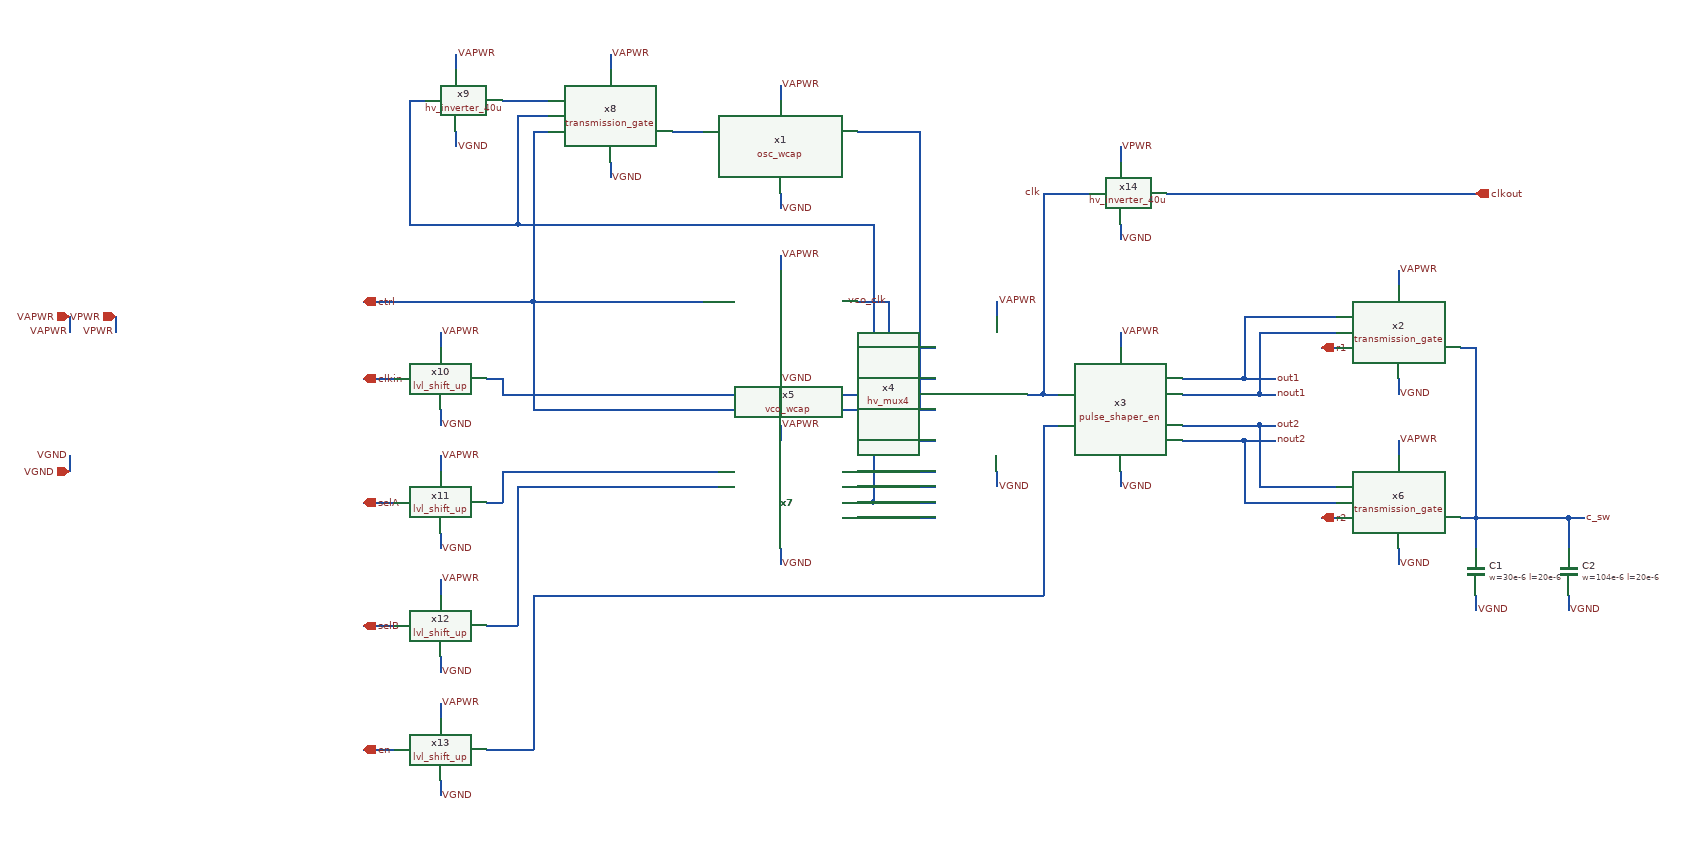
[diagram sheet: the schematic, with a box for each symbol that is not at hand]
v {xschem version=3.4.8RC file_version=1.3}
G {}
K {}
V {}
S {}
F {}
E {}
N 560 260 560 280 {lab=VGND}
N -1260 80 -1260 100 {lab=VGND}
N -1260 -100 -1260 -80 {lab=VAPWR}
N 540 -60 560 -60 {lab=c_sw
}
N 360 -60 380 -60 {lab=r1
}
N 0 0 20 0 {lab=clk}
N 540 160 560 160 {lab=c_sw
}
N 360 160 380 160 {lab=r2
}
N 560 160 560 200 {lab=c_sw}
N 560 -60 560 160 {lab=c_sw
}
N 260 -100 380 -100 {lab=out1}
N -660 -120 -440 -120 {lab=ctrl}
N 180 -20 260 -20 {lab=out1}
N 260 -100 260 -20 {lab=out1}
N 180 0 280 0 {lab=nout1}
N 280 -80 280 0 {lab=nout1}
N 280 -80 380 -80 {lab=nout1}
N 180 60 260 60 {lab=nout2}
N 260 60 260 140 {lab=nout2}
N 260 140 380 140 {lab=nout2}
N 180 40 280 40 {lab=out2}
N 280 40 280 120 {lab=out2}
N 280 120 380 120 {lab=out2}
N -240 -120 -200 -120 {lab=#net1}
N -200 -120 -200 -20 {lab=#net1}
N -200 -20 -140 -20 {lab=#net1}
N -240 -340 -160 -340 {lab=#net2}
N -160 -340 -160 20 {lab=#net2}
N 0 40 0 260 {lab=#net3}
N 0 40 20 40 {lab=#net3}
N -260 100 -140 100 {lab=#net4}
N -260 120 -140 120 {lab=#net5}
N -220 140 -140 140 {lab=#net6}
N -260 160 -140 160 {lab=#net7}
N -880 -120 -660 -120 {lab=ctrl}
N -480 -340 -440 -340 {lab=#net8}
N -700 100 -420 100 {lab=#net9}
N -680 120 -420 120 {lab=#net10}
N -660 260 0 260 {lab=#net3}
N -660 -120 -660 20 {lab=ctrl}
N -660 20 -180 20 {lab=ctrl}
N -180 20 -180 60 {lab=ctrl}
N -660 -340 -660 -120 {lab=ctrl}
N -660 -340 -640 -340 {lab=ctrl}
N -680 -220 -220 -220 {lab=#net6}
N -820 -380 -820 -220 {lab=#net6}
N -820 -380 -800 -380 {lab=#net6}
N -680 -360 -680 -220 {lab=#net6}
N -820 -220 -680 -220 {lab=#net6}
N -680 -360 -640 -360 {lab=#net6}
N -700 -380 -640 -380 {lab=#net11}
N -760 -340 -760 -320 {lab=VGND}
N -760 -440 -760 -420 {lab=VAPWR}
N 680 260 680 280 {lab=VGND}
N 560 160 680 160 {lab=c_sw}
N 680 160 680 200 {lab=c_sw}
N 0 -260 0 0 {lab=clk}
N -20 0 0 0 {lab=clk}
N -880 -20 -840 -20 {lab=clkin}
N -880 140 -840 140 {lab=selA}
N -880 300 -840 300 {lab=selB}
N -880 460 -840 460 {lab=en}
N -720 -20 -700 -20 {lab=#net12}
N -660 260 -660 460 {lab=#net3}
N -720 460 -660 460 {lab=#net3}
N -720 300 -680 300 {lab=#net10}
N -680 120 -680 300 {lab=#net10}
N -700 100 -700 140 {lab=#net9}
N -720 140 -700 140 {lab=#net9}
N 100 -220 100 -200 {lab=VGND}
N 100 -320 100 -300 {lab=VPWR}
N 0 -260 60 -260 {lab=clk}
N 160 -260 560 -260 {lab=clkout}
N -1200 -100 -1200 -80 {lab=VPWR}
N -560 -440 -560 -420 {lab=VAPWR}
N -560 -300 -560 -280 {lab=VGND}
N -340 -400 -340 -380 {lab=VAPWR}
N -340 -260 -340 -240 {lab=VGND}
N -340 -180 -340 -160 {lab=VAPWR}
N -340 -40 -340 -20 {lab=VGND}
N 460 -160 460 -140 {lab=VAPWR}
N 460 -20 460 0 {lab=VGND}
N 460 60 460 80 {lab=VAPWR}
N 460 200 460 220 {lab=VGND}
N -340 40 -340 60 {lab=VAPWR}
N -340 200 -340 220 {lab=VGND}
N -780 -80 -780 -60 {lab=VAPWR}
N -780 20 -780 40 {lab=VGND}
N -780 80 -780 100 {lab=VAPWR}
N -780 180 -780 200 {lab=VGND}
N -780 240 -780 260 {lab=VAPWR}
N -780 340 -780 360 {lab=VGND}
N -780 400 -780 420 {lab=VAPWR}
N -780 500 -780 520 {lab=VGND}
N -60 -120 -60 -100 {lab=VAPWR}
N -60 100 -60 120 {lab=VGND}
N 100 -80 100 -60 {lab=VAPWR}
N 100 100 100 120 {lab=VGND}
N -180 60 -140 60 {lab=ctrl}
N -160 20 -140 20 {lab=#net2}
N -700 -20 -700 -0 {lab=#net12}
N -700 -0 -180 -0 {lab=#net12}
N -180 -60 -180 0 {lab=#net12}
N -180 -60 -140 -60 {lab=#net12}
N -220 -220 -220 140 {lab=#net6}
N -260 140 -220 140 {lab=#net6}
N 680 160 700 160 {lab=c_sw}
N 280 0 300 0 {lab=nout1
}
N 280 40 300 40 {lab=out2
}
N 260 -20 300 -20 {lab=out1}
N 260 60 300 60 {lab=nout2}
C {iopin.sym} 360 -60 0 1 {name=p5 lab=r1}
C {iopin.sym} 360 160 0 1 {name=p6 lab=r2}
C {devices/iopin.sym} -1260 -100 3 0 {name=p11 lab=VAPWR}
C {devices/iopin.sym} -1260 100 1 0 {name=p7 lab=VGND}
C {lab_pin.sym} -1260 -80 3 0 {name=p8 sig_type=std_logic lab=VAPWR}
C {lab_pin.sym} -1260 80 3 1 {name=p9 sig_type=std_logic lab=VGND}
C {sg13cmos5l_pr/cap_cmomi.sym} 560 230 0 0 {name=C1
model=cap_cmomi
w=30e-6
l=20e-6
mmin=1
mmax=4
feed=double
subblock=0
m=1
mm_ok=1
spiceprefix=X
}
C {transmission_gate.sym} 460 -80 0 0 {name=x2
}
C {transmission_gate.sym} 460 140 0 0 {name=x6
}
C {ipin.sym} -880 -120 2 1 {name=p2 lab=ctrl}
C {lab_pin.sym} 0 -260 1 0 {name=p3 sig_type=std_logic lab=clk
}
C {hv_mux4.sym} -80 0 0 0 {name=x4
}
C {lab_pin.sym} -200 -120 1 0 {name=p26 sig_type=std_logic lab=vco_clk
spice_ignore=true}
C {pulse_shaper_en.sym} 100 20 0 0 {name=x3}
C {hv_binary_decoder4.sym} -340 140 0 0 {name=x7}
C {noconn.sym} -440 -80 0 0 {name=l1}
C {noconn.sym} -440 -320 0 0 {name=l2}
C {noconn.sym} -440 -300 0 0 {name=l3}
C {noconn.sym} -240 -320 0 1 {name=l4}
C {noconn.sym} -240 -80 0 1 {name=l5}
C {transmission_gate.sym} -560 -360 0 0 {name=x8
}
C {hv_inverter_40u.sym} -760 -380 0 0 {name=x9}
C {sg13cmos5l_pr/cap_cmomi.sym} 680 230 0 0 {name=C2
model=cap_cmomi
w=104e-6
l=20e-6
mmin=1
mmax=4
feed=double
subblock=0
m=1
mm_ok=1
spiceprefix=X
}
C {ipin.sym} -880 -20 2 1 {name=p34 lab=clkin}
C {ipin.sym} -880 140 2 1 {name=p35 lab=selA}
C {ipin.sym} -880 300 2 1 {name=p36 lab=selB}
C {ipin.sym} -880 460 2 1 {name=p37 lab=en}
C {opin.sym} 560 -260 0 0 {name=p21 lab=clkout}
C {lvl_shift_up.sym} -780 -20 0 0 {name=x10}
C {lvl_shift_up.sym} -780 140 0 0 {name=x11}
C {lvl_shift_up.sym} -780 300 0 0 {name=x12}
C {lvl_shift_up.sym} -780 460 0 0 {name=x13}
C {hv_inverter_40u.sym} 100 -260 0 0 {name=x14}
C {devices/iopin.sym} -1200 -100 3 0 {name=p45 lab=VPWR}
C {lab_pin.sym} -1200 -80 3 0 {name=p46 sig_type=std_logic lab=VPWR}
C {lab_pin.sym} 100 -320 0 1 {name=p47 sig_type=std_logic lab=VPWR}
C {lab_pin.sym} -760 -440 0 1 {name=p43 sig_type=std_logic lab=VAPWR}
C {lab_pin.sym} -560 -440 0 1 {name=p23 sig_type=std_logic lab=VAPWR}
C {lab_pin.sym} -760 -320 0 1 {name=p30 sig_type=std_logic lab=VGND}
C {lab_pin.sym} -560 -280 0 1 {name=p27 sig_type=std_logic lab=VGND}
C {lab_pin.sym} -340 -400 0 1 {name=p4 sig_type=std_logic lab=VAPWR}
C {lab_pin.sym} -340 -240 0 1 {name=p17 sig_type=std_logic lab=VGND}
C {lab_pin.sym} -340 -180 0 1 {name=p19 sig_type=std_logic lab=VAPWR}
C {lab_pin.sym} -340 -20 0 1 {name=p20 sig_type=std_logic lab=VGND}
C {lab_pin.sym} 460 -160 0 1 {name=p12 sig_type=std_logic lab=VAPWR}
C {lab_pin.sym} 460 0 0 1 {name=p14 sig_type=std_logic lab=VGND}
C {lab_pin.sym} 460 60 0 1 {name=p13 sig_type=std_logic lab=VAPWR}
C {lab_pin.sym} 460 220 0 1 {name=p22 sig_type=std_logic lab=VGND}
C {lab_pin.sym} -340 40 0 1 {name=p28 sig_type=std_logic lab=VAPWR}
C {lab_pin.sym} -340 220 0 1 {name=p29 sig_type=std_logic lab=VGND}
C {lab_pin.sym} -780 -80 0 1 {name=p24 sig_type=std_logic lab=VAPWR}
C {lab_pin.sym} -780 40 0 1 {name=p25 sig_type=std_logic lab=VGND}
C {lab_pin.sym} -780 80 0 1 {name=p31 sig_type=std_logic lab=VAPWR}
C {lab_pin.sym} -780 200 0 1 {name=p32 sig_type=std_logic lab=VGND}
C {lab_pin.sym} -780 240 0 1 {name=p38 sig_type=std_logic lab=VAPWR}
C {lab_pin.sym} -780 360 0 1 {name=p39 sig_type=std_logic lab=VGND}
C {lab_pin.sym} -780 400 0 1 {name=p40 sig_type=std_logic lab=VAPWR}
C {lab_pin.sym} -780 520 0 1 {name=p41 sig_type=std_logic lab=VGND}
C {lab_pin.sym} -60 -120 0 1 {name=p18 sig_type=std_logic lab=VAPWR}
C {lab_pin.sym} -60 120 0 1 {name=p16 sig_type=std_logic lab=VGND}
C {lab_pin.sym} 100 -80 0 1 {name=p1 sig_type=std_logic lab=VAPWR}
C {lab_pin.sym} 100 120 0 1 {name=p10 sig_type=std_logic lab=VGND}
C {lab_pin.sym} 560 280 0 1 {name=p15 sig_type=std_logic lab=VGND}
C {lab_pin.sym} 680 280 0 1 {name=p33 sig_type=std_logic lab=VGND}
C {lab_pin.sym} 100 -200 0 1 {name=p42 sig_type=std_logic lab=VGND}
C {lab_pin.sym} 700 160 0 1 {name=p44 sig_type=std_logic lab=c_sw}
C {devices/lab_pin.sym} 300 -20 0 1 {name=l15 sig_type=std_logic lab=out1
}
C {devices/lab_pin.sym} 300 0 0 1 {name=l6 sig_type=std_logic lab=nout1
}
C {devices/lab_pin.sym} 300 60 0 1 {name=l17 sig_type=std_logic lab=nout2
}
C {devices/lab_pin.sym} 300 40 0 1 {name=l18 sig_type=std_logic lab=out2
}
C {osc_wcap.sym} -340 -320 0 0 {name=x1}
C {vco_wcap.sym} -340 -100 0 0 {name=x5}
